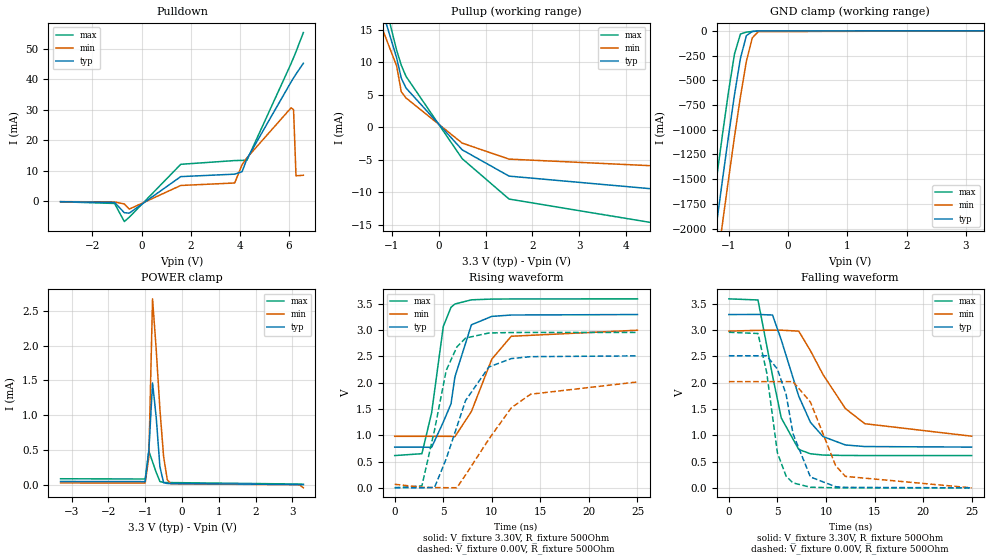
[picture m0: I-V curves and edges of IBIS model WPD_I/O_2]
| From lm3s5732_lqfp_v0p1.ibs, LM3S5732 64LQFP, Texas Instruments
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[Model]   WPD_I/O_2
Model_type   I/O
Vinl = 1.26
Vinh = 2.04
Vmeas = 1.65
| variable   typ   min   max
C_comp   9.739pF   9.739pF   9.803pF
[Model Spec]
Vinh+   1.91   1.78   2.04
Vinh-   1.90   1.76   2.03
Vinl+   1.40   1.27   1.54
Vinl-   1.39   1.26   1.53
| variable   typ   min   max
[Temperature Range]  25   85   -40
[Voltage Range]   3.3V   3.0V   3.6V
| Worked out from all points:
|   slope of the pulldown table from 0 to 0.495 V, typ, clamps not added: 143 ohm
|   slope of the pullup table from 0 to 0.495 V, typ, clamps not added: 143 ohm
|   GND clamp passes 1 mA (typ) near -0.48 V on its own axis
|   POWER clamp passes 1 mA (typ) near -0.71 V on its own axis
|   falling waveform, V_fixture 3.30V, R_fixture 500Ohm: 20-80 % time 2.85ns typ, 4.24ns min, 1.93ns max; typ from 3.29 V to 0.774 V
|   rising waveform, V_fixture 3.30V, R_fixture 500Ohm: 20-80 % time 1.99ns typ, 2.79ns min, 1.46ns max; typ from 0.774 V to 3.3 V
|   falling waveform, V_fixture 0.00V, R_fixture 500Ohm: 20-80 % time 1.94ns typ, 2.63ns min, 1.43ns max; typ from 2.51 V to 0 V
|   rising waveform, V_fixture 0.00V, R_fixture 500Ohm: 20-80 % time 3.04ns typ, 4.58ns min, 2ns max; typ from 0.005 V to 2.51 V
[Pulldown]
|  Voltage   I(typ)   I(min)   I(max)
-3.3V     -64.09uA   -36.38uA   -91.03uA
-1.1V     -317.9uA   -146.8uA   -640.8uA
-700mV    -3.676mA   -803.4uA   -6.573mA
-500mV    -3.809mA   -2.499mA   -5.157mA
1.6V      8.15mA     5.248mA    12.18mA
3.8V      8.955mA    6.06mA     13.41mA
4.1V      9.768mA    12.04mA    13.46mA
4.3V      13.97mA    14.32mA    13.53mA
6.1V      39.17mA    30.69mA    45.2mA
6.2V      40.46mA    30.09mA    47.11mA
6.3V      41.74mA    8.408mA    49.08mA
6.6V      45.27mA    8.593mA    55.33mA
[Pullup]
|  Voltage   I(typ)   I(min)   I(max)
-3.3V     58.83mA    18.64mA    75.06mA
-1.5V     24.38mA    20.24mA    28.72mA
-1.3V     20mA       16.77mA    23.28mA
-1.2V     17.78mA    15.02mA    20.52mA
-900mV    10.66mA    9.402mA    11.83mA
-800mV    7.53mA     5.414mA    9.501mA
-700mV    6.009mA    4.481mA    7.802mA
500mV     -3.505mA   -2.469mA   -4.866mA
1.5V      -7.548mA   -4.932mA   -11.08mA
5V        -9.793mA   -6.102mA   -15.25mA
6V        -12.34mA   -7.492mA   -19.35mA
6.6V      -15.07mA   -8.994mA   -23.96mA
[GND Clamp]
|  Voltage   I(typ)   I(min)   I(max)
-3.3V     -11.73A    -12.14A    -11.32A
-1.4V     -2.85A     -3.29A     -2.391A
-1.3V     -2.393A    -2.835A    -1.933A
-1.2V     -1.942A    -2.383A    -1.481A
-1.1V     -1.496A    -1.937A    -1.038A
-1V       -1.061A    -1.498A    -612.1mA
-900mV    -646.5mA   -1.071A    -233.9mA
-800mV    -278.2mA   -665.9mA   -32.18mA
-700mV    -49.13mA   -307.7mA   -12.5mA
-600mV    -5.766mA   -70.86mA   -6.513mA
-500mV    -1.212mA   -8.171mA   -2.264mA
3.3V      16.11uA    11.95uA    29.77uA
[POWER Clamp]
|  Voltage   I(typ)   I(min)   I(max)
-3.3V     45.95uA    24.7uA     84.99uA
-1V       43.79uA    23.54uA    81.02uA
-900mV    497uA      400.5uA    481.3uA
-800mV    1.464mA    2.675mA    328uA
-700mV    965.7uA    1.944mA    175.8uA
-600mV    259.3uA    1.087mA    45.21uA
-500mV    29.01uA    407.8uA    31.06uA
-400mV    16.44uA    70.61uA    29.85uA
-300mV    16.12uA    11.95uA    29.79uA
3.1V      2.407uA    -925.9nA   9.193uA
3.2V      1.227uA    -4.064uA   7.471uA
3.3V      -117.9pA   -46.06uA   5.69uA
[Ramp]
| variable   typ   min   max
dV/dt_f   1.51/2.85n   1.20/4.24n   1.79/1.93n
dV/dt_r   1.50/3.04n   1.17/4.58n   1.77/2.00n
R_load = 500Ohm
[Falling Waveform]
V_fixture = 3.30V
V_fixture_min = 3.00V
V_fixture_max = 3.60V
R_fixture = 500Ohm
|   Time   V(typ)   V(min)   V(max)
0s        3.293V     2.978V     3.591V
3ns       3.295V     2.993V     3.57V
4.5ns     3.284V     2.995V     2.131V
5.4ns     2.81V      2.996V     1.328V
7.2ns     1.741V     2.978V     729.6mV
8.4ns     1.246V     2.607V     647.5mV
9.7ns     974.5mV    2.152V     623.1mV
12ns      815mV      1.507V     615.1mV
14ns      784.7mV    1.219V     614.3mV
25ns      774.3mV    981.9mV    614.1mV
[Rising Waveform]
V_fixture = 3.30V
V_fixture_min = 3.00V
V_fixture_max = 3.60V
R_fixture = 500Ohm
|   Time   V(typ)   V(min)   V(max)
0s        774.3mV    980.2mV    614.1mV
2.8ns     774.3mV    980mV      649.9mV
3.8ns     770.2mV    980mV      1.426V
5ns       1.249V     979.9mV    3.068V
5.8ns     1.6V       979.6mV    3.434V
6.2ns     2.111V     973mV      3.496V
7.9ns     3.101V     1.453V     3.576V
10ns      3.261V     2.448V     3.59V
12ns      3.287V     2.883V     3.592V
25ns      3.296V     2.998V     3.594V
[Falling Waveform]
V_fixture = 0.00V
V_fixture_min = 0.00V
V_fixture_max = 0.00V
R_fixture = 500Ohm
|   Time   V(typ)   V(min)   V(max)
0s        2.51V      2.018V     2.956V
3ns       2.51V      2.018V     2.933V
3.9ns     2.51V      2.018V     2.19V
5ns       2.258V     2.018V     667.7mV
5.9ns     1.774V     2.018V     221mV
6.6ns     1.032V     2.019V     94.37mV
8.4ns     206.6mV    1.631V     11.33mV
11ns      21.52mV    421.7mV    712.2uV
12ns      9.312mV    217.6mV    301.3uV
25ns      30.04uV    131.8uV    20.33uV
[Rising Waveform]
V_fixture = 0.00V
V_fixture_min = 0.00V
V_fixture_max = 0.00V
R_fixture = 500Ohm
|   Time   V(typ)   V(min)   V(max)
0s        4.944mV    67.69mV    205.5uV
2.8ns     491.7uV    11.6mV     38.62mV
4.1ns     7.127mV    5.277mV    1.099V
5.3ns     550.3mV    2.605mV    2.232V
6.4ns     1.16V      2.696mV    2.679V
7.3ns     1.663V     245.8mV    2.849V
9.7ns     2.299V     928mV      2.945V
12ns      2.458V     1.522V     2.954V
14ns      2.495V     1.781V     2.955V
25ns      2.51V      2.014V     2.956V
